VERSION 5.8 ;
BUSBITCHARS "<>" ;
DIVIDERCHAR "/" ;

UNITS
   DATABASE MICRONS 1000 ;
END UNITS

LAYER M1
   TYPE ROUTING ;
   WIDTH 1 ;
   PITCH 2 ;
   DIRECTION HORIZONTAL ;
END M1

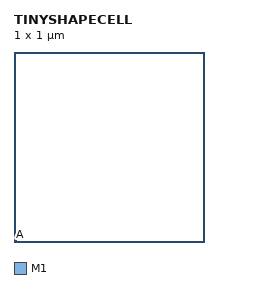
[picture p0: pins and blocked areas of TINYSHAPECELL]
MACRO TINYSHAPECELL
   CLASS CORE ;
   SIZE 1 BY 1 ;

   PIN A
      DIRECTION INPUT ;
      PORT
         LAYER M1 ;
         RECT 0.01 0.01 0.011 0.011 ;
      END
   END A
END TINYSHAPECELL
